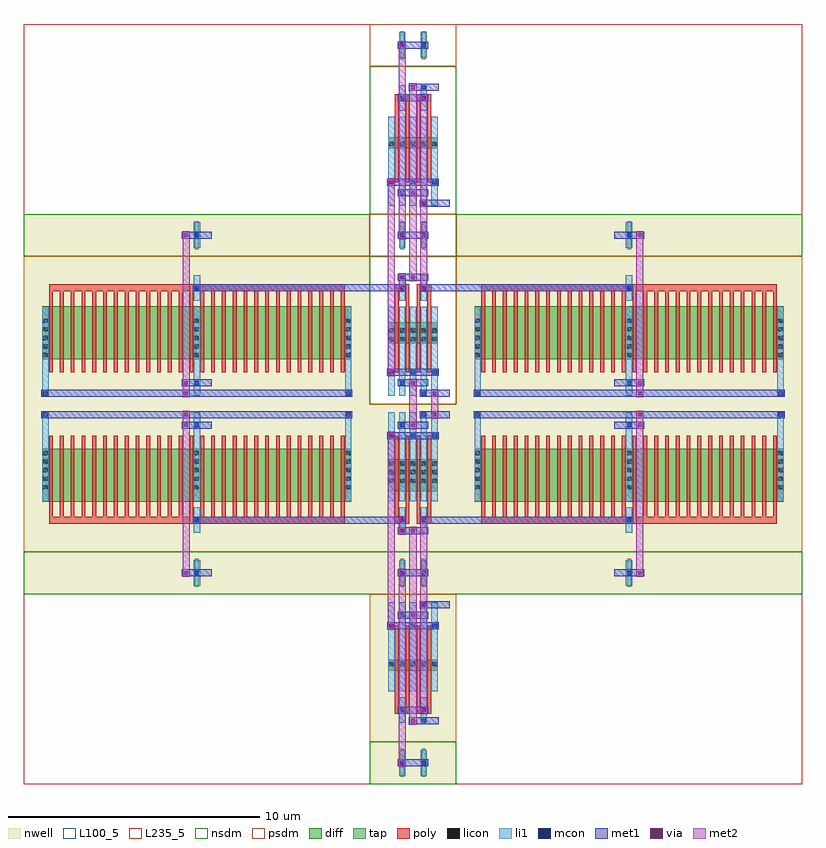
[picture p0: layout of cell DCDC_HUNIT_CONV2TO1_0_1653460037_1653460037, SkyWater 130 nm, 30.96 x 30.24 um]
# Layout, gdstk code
from math import pi, radians
import gdstk
lib = gdstk.Library(unit=1e-6, precision=1e-09)
def R(c, l, rs):  # rectangles x0, y0, x1, y1
    for r in rs: c.add(gdstk.rectangle(r[:2], r[2:], *l))
def A(c, l, x, y, w, h, nx, ny, dx, dy):  # array of equal rectangles
    R(c, l, [(x+i*dx, y+j*dy, x+i*dx+w, y+j*dy+h) for i in range(nx) for j in range(ny)])
def P(c, l, *ps):  # polygons
    for p in ps: c.add(gdstk.Polygon(p, *l))
nwell = (64, 20)
diff = (65, 20)
tap = (65, 44)
poly = (66, 20)
licon = (66, 44)
li1 = (67, 20)
mcon = (67, 44)
met1 = (68, 20)
via = (68, 44)
met2 = (69, 20)
nsdm = (93, 44)
psdm = (94, 20)
L100_5 = (100, 5)
L235_5 = (235, 5)

ccp_pmos_b_53083828_x1_y = lib.new_cell('CCP_PMOS_B_53083828_X1_Y1_1653460036_1653460037_1653460037_1653460037')
R(ccp_pmos_b_53083828_x1_y, nwell, [(0,0,3.44,7.56)])
R(ccp_pmos_b_53083828_x1_y, diff, [(0.735,2.625,2.705,3.045)])
R(ccp_pmos_b_53083828_x1_y, tap, [(1.205,6.16,1.375,7.28), (2.065,6.16,2.235,7.28)])
A(ccp_pmos_b_53083828_x1_y, poly, 1, 1.26, 0.15, 3.36, 4, 1, 0.43, 0)
R(ccp_pmos_b_53083828_x1_y, poly, [(1,4.485,1.58,4.755), (1.86,4.485,2.44,4.755)])
A(ccp_pmos_b_53083828_x1_y, licon, 0.775, 2.705, 0.17, 0.17, 3, 1, 0.43, 0)
A(ccp_pmos_b_53083828_x1_y, licon, 1.635, 2.705, 0.17, 0.17, 3, 1, 0.43, 0)
R(ccp_pmos_b_53083828_x1_y, licon, [(1.205,4.535,1.375,4.705), (2.065,4.535,2.235,4.705), (1.205,6.635,1.375,6.805), (2.065,6.635,2.235,6.805)])
A(ccp_pmos_b_53083828_x1_y, li1, 0.735, 0.335, 0.25, 3.53, 5, 1, 0.43, 0)
R(ccp_pmos_b_53083828_x1_y, li1, [(1.165,4.115,1.415,5.125), (2.025,4.115,2.275,5.125), (1.165,6.215,1.415,7.225), (2.025,6.215,2.275,7.225)])
A(ccp_pmos_b_53083828_x1_y, mcon, 0.775, 1.175, 0.17, 0.17, 3, 1, 0.86, 0)
R(ccp_pmos_b_53083828_x1_y, mcon, [(1.205,0.335,1.375,0.505), (2.065,0.755,2.235,0.925), (2.065,4.535,2.235,4.705), (1.205,4.955,1.375,5.125), (1.205,6.635,1.375,6.805), (2.065,6.635,2.235,6.805)])
R(ccp_pmos_b_53083828_x1_y, met1, [(0.26,0.28,1.46,0.56), (1.12,0.7,2.32,0.98), (0.69,1.12,2.75,1.4), (1.12,4.48,2.32,4.76), (0.69,4.9,1.89,5.18), (1.12,6.58,2.32,6.86)])
R(ccp_pmos_b_53083828_x1_y, via, [(1.215,0.345,1.365,0.495), (1.645,0.765,1.795,0.915), (1.215,4.545,1.365,4.695), (1.645,4.965,1.795,5.115)])
R(ccp_pmos_b_53083828_x1_y, met2, [(1.15,0.26,1.43,4.78), (1.58,0.68,1.86,5.2)])
R(ccp_pmos_b_53083828_x1_y, nsdm, [(0,5.88,3.44,7.56)])
R(ccp_pmos_b_53083828_x1_y, psdm, [(0,0,3.44,5.88)])
R(ccp_pmos_b_53083828_x1_y, L100_5, [(0,0,3.44,7.56)])

dp_pmos_b_25364157_x1_y1 = lib.new_cell('DP_PMOS_B_25364157_X1_Y1_1653460038_1653460037_1653460037_1653460037')
R(dp_pmos_b_25364157_x1_y1, nwell, [(0,0,3.44,7.56)])
R(dp_pmos_b_25364157_x1_y1, diff, [(0.735,2.205,2.705,3.465)])
R(dp_pmos_b_25364157_x1_y1, tap, [(1.205,6.16,1.375,7.28), (2.065,6.16,2.235,7.28)])
A(dp_pmos_b_25364157_x1_y1, poly, 1, 1.26, 0.15, 3.36, 4, 1, 0.43, 0)
R(dp_pmos_b_25364157_x1_y1, poly, [(1,4.485,1.58,4.755), (1.86,4.485,2.44,4.755)])
A(dp_pmos_b_25364157_x1_y1, licon, 0.775, 2.285, 0.17, 0.17, 3, 3, 0.43, 0.34)
A(dp_pmos_b_25364157_x1_y1, licon, 1.635, 2.285, 0.17, 0.17, 3, 3, 0.43, 0.34)
R(dp_pmos_b_25364157_x1_y1, licon, [(1.205,4.535,1.375,4.705), (2.065,4.535,2.235,4.705), (1.205,6.635,1.375,6.805), (2.065,6.635,2.235,6.805)])
A(dp_pmos_b_25364157_x1_y1, li1, 0.735, 0.335, 0.25, 3.53, 5, 1, 0.43, 0)
R(dp_pmos_b_25364157_x1_y1, li1, [(1.165,4.115,1.415,5.125), (2.025,4.115,2.275,5.125), (1.165,6.215,1.415,7.225), (2.025,6.215,2.275,7.225)])
A(dp_pmos_b_25364157_x1_y1, mcon, 0.775, 1.175, 0.17, 0.17, 3, 1, 0.86, 0)
R(dp_pmos_b_25364157_x1_y1, mcon, [(1.205,0.335,1.375,0.505), (2.065,0.755,2.235,0.925), (1.205,4.535,1.375,4.705), (2.065,4.955,2.235,5.125), (1.205,6.635,1.375,6.805), (2.065,6.635,2.235,6.805)])
R(dp_pmos_b_25364157_x1_y1, met1, [(0.26,0.28,1.46,0.56), (1.12,0.7,2.32,0.98), (0.69,1.12,2.75,1.4), (0.26,4.48,1.46,4.76), (1.12,4.9,2.32,5.18), (1.12,6.58,2.32,6.86)])
R(dp_pmos_b_25364157_x1_y1, nsdm, [(0,5.88,3.44,7.56)])
R(dp_pmos_b_25364157_x1_y1, psdm, [(0,0,3.44,5.88)])
R(dp_pmos_b_25364157_x1_y1, L100_5, [(0,0,3.44,7.56)])

dcap_pmos_57222488_x1_y1 = lib.new_cell('DCAP_PMOS_57222488_X1_Y1_1653460037_1653460037_1653460037_1653460037')
R(dcap_pmos_57222488_x1_y1, nwell, [(0,0,13.76,7.56)])
R(dcap_pmos_57222488_x1_y1, diff, [(0.735,1.785,13.025,3.885)])
R(dcap_pmos_57222488_x1_y1, tap, [(6.795,6.16,6.965,7.28)])
A(dcap_pmos_57222488_x1_y1, poly, 1, 1.26, 0.15, 3.36, 28, 1, 0.43, 0)
R(dcap_pmos_57222488_x1_y1, poly, [(1,4.485,12.76,4.755)])
A(dcap_pmos_57222488_x1_y1, licon, 0.775, 1.865, 0.17, 0.17, 3, 5, 6.02, 0.34)
R(dcap_pmos_57222488_x1_y1, licon, [(6.795,4.535,6.965,4.705), (6.795,6.635,6.965,6.805)])
A(dcap_pmos_57222488_x1_y1, li1, 0.735, 0.335, 0.25, 3.53, 3, 1, 6.02, 0)
R(dcap_pmos_57222488_x1_y1, li1, [(6.755,4.115,7.005,5.125), (6.755,6.215,7.005,7.225)])
R(dcap_pmos_57222488_x1_y1, mcon, [(0.775,0.335,0.945,0.505), (12.815,0.335,12.985,0.505), (6.795,0.755,6.965,0.925), (6.795,4.535,6.965,4.705), (6.795,6.635,6.965,6.805)])
R(dcap_pmos_57222488_x1_y1, met1, [(0.69,0.28,13.07,0.56), (6.28,0.7,7.48,0.98), (5.85,4.48,7.05,4.76), (6.28,6.58,7.48,6.86)])
R(dcap_pmos_57222488_x1_y1, via, [(7.235,0.345,7.385,0.495), (7.235,0.765,7.385,0.915), (7.235,6.645,7.385,6.795)])
R(dcap_pmos_57222488_x1_y1, met2, [(7.17,0.26,7.45,6.88)])
R(dcap_pmos_57222488_x1_y1, nsdm, [(0,5.88,13.76,7.56)])
R(dcap_pmos_57222488_x1_y1, psdm, [(0,0,13.76,5.88)])
R(dcap_pmos_57222488_x1_y1, L100_5, [(0,0,13.76,7.56)])

dcdc_xsw_pmos_0_16534600 = lib.new_cell('DCDC_XSW_PMOS_0_1653460037_1653460037_1653460037')
R(dcdc_xsw_pmos_0_16534600, met1, [(14.89,0.7,15.21,0.98), (14.89,0.7,15.21,0.98), (14.46,6.16,14.78,6.44), (14.46,6.16,14.78,6.44), (14.89,8.26,15.21,8.54), (14.89,8.26,15.21,8.54), (14.89,9.94,15.21,10.22), (14.89,9.94,15.21,10.22), (15.32,9.94,15.64,10.22), (15.32,9.94,15.64,10.22), (15.32,9.94,15.64,10.22), (15.32,9.94,15.64,10.22), (7.74,10.36,15.05,10.64), (14.89,10.36,15.21,10.64), (14.89,10.36,15.21,10.64), (15.75,10.36,16.07,10.64), (15.75,10.36,16.07,10.64), (15.75,10.36,16.07,10.64), (15.75,10.36,16.07,10.64), (16.77,10.36,23.22,10.64), (14.46,13.72,14.78,14), (14.46,13.72,14.78,14)])
P(dcdc_xsw_pmos_0_16534600, met1, [(0,0),(0,0),(0,0),(0,0)],
  [(0,0),(0,0),(0,0),(0,0)],
  [(0,0),(0,0),(0,0),(0,0)],
  [(0,0),(0,0),(0,0),(0,0)],
  [(0,0),(0,0),(0,0),(0,0)],
  [(0,0),(0,0),(0,0),(0,0)],
  [(0,0),(0,0),(0,0),(0,0)],
  [(0,0),(0,0),(0,0),(0,0)],
  [(0,0),(0,0),(0,0),(0,0)],
  [(0,0),(0,0),(0,0),(0,0)])
R(dcdc_xsw_pmos_0_16534600, via, [(14.975,0.765,15.125,0.915), (14.975,0.765,15.125,0.915), (14.545,6.225,14.695,6.375), (14.545,6.225,14.695,6.375), (14.975,8.325,15.125,8.475), (14.975,8.325,15.125,8.475), (14.975,10.005,15.125,10.155), (14.975,10.005,15.125,10.155), (15.405,10.005,15.555,10.155), (15.405,10.005,15.555,10.155), (15.405,10.005,15.555,10.155), (15.405,10.005,15.555,10.155), (14.975,10.425,15.125,10.575), (14.975,10.425,15.125,10.575), (15.835,10.425,15.985,10.575), (15.835,10.425,15.985,10.575), (15.835,10.425,15.985,10.575), (15.835,10.425,15.985,10.575), (14.545,13.785,14.695,13.935), (14.545,13.785,14.695,13.935)])
R(dcdc_xsw_pmos_0_16534600, met2, [(14.91,0.68,15.19,1), (14.91,0.68,15.19,1), (14.91,0.84,15.19,8.4), (14.48,6.14,14.76,6.46), (14.48,6.14,14.76,6.46), (14.48,6.3,14.76,13.86), (15.34,6.72,15.62,10.08), (15.77,7.14,16.05,10.5), (14.91,8.24,15.19,8.56), (14.91,8.24,15.19,8.56), (14.91,9.92,15.19,10.24), (14.91,9.92,15.19,10.24), (15.34,9.92,15.62,10.24), (15.34,9.92,15.62,10.24), (15.34,9.92,15.62,10.24), (15.34,9.92,15.62,10.24), (14.91,10.08,15.19,10.5), (14.91,10.34,15.19,10.66), (14.91,10.34,15.19,10.66), (15.77,10.34,16.05,10.66), (15.77,10.34,16.05,10.66), (15.77,10.34,16.05,10.66), (15.77,10.34,16.05,10.66), (14.48,13.7,14.76,14.02), (14.48,13.7,14.76,14.02)])
P(dcdc_xsw_pmos_0_16534600, met2, [(0,0),(0,0),(0,0),(0,0)],
  [(0,0),(0,0),(0,0),(0,0)],
  [(0,0),(0,0),(0,0),(0,0)],
  [(0,0),(0,0),(0,0),(0,0)])
R(dcdc_xsw_pmos_0_16534600, L235_5, [(0,0,30.96,15.12)])
dcdc_xsw_pmos_0_16534600.add(gdstk.Reference(ccp_pmos_b_53083828_x1_y, (17.2,7.56), rotation=pi))
dcdc_xsw_pmos_0_16534600.add(gdstk.Reference(dp_pmos_b_25364157_x1_y1, (17.2,15.12), rotation=pi))
dcdc_xsw_pmos_0_16534600.add(gdstk.Reference(dcap_pmos_57222488_x1_y1, (17.2,15.12), x_reflection=True))
dcdc_xsw_pmos_0_16534600.add(gdstk.Reference(dcap_pmos_57222488_x1_y1, (13.76,15.12), rotation=pi))

ccp_nmos_b_26073270_x1_y = lib.new_cell('CCP_NMOS_B_26073270_X1_Y1_1653460036_1653460036_1653460037_1653460037')
R(ccp_nmos_b_26073270_x1_y, diff, [(0.735,2.625,2.705,3.045)])
R(ccp_nmos_b_26073270_x1_y, tap, [(1.205,6.16,1.375,7.28), (2.065,6.16,2.235,7.28)])
A(ccp_nmos_b_26073270_x1_y, poly, 1, 1.26, 0.15, 3.36, 4, 1, 0.43, 0)
R(ccp_nmos_b_26073270_x1_y, poly, [(1,4.485,1.58,4.755), (1.86,4.485,2.44,4.755)])
A(ccp_nmos_b_26073270_x1_y, licon, 0.775, 2.705, 0.17, 0.17, 3, 1, 0.43, 0)
A(ccp_nmos_b_26073270_x1_y, licon, 1.635, 2.705, 0.17, 0.17, 3, 1, 0.43, 0)
R(ccp_nmos_b_26073270_x1_y, licon, [(1.205,4.535,1.375,4.705), (2.065,4.535,2.235,4.705), (1.205,6.635,1.375,6.805), (2.065,6.635,2.235,6.805)])
A(ccp_nmos_b_26073270_x1_y, li1, 0.735, 0.335, 0.25, 3.53, 5, 1, 0.43, 0)
R(ccp_nmos_b_26073270_x1_y, li1, [(1.165,4.115,1.415,5.125), (2.025,4.115,2.275,5.125), (1.165,6.215,1.415,7.225), (2.025,6.215,2.275,7.225)])
A(ccp_nmos_b_26073270_x1_y, mcon, 0.775, 1.175, 0.17, 0.17, 3, 1, 0.86, 0)
R(ccp_nmos_b_26073270_x1_y, mcon, [(1.205,0.335,1.375,0.505), (2.065,0.755,2.235,0.925), (2.065,4.535,2.235,4.705), (1.205,4.955,1.375,5.125), (1.205,6.635,1.375,6.805), (2.065,6.635,2.235,6.805)])
R(ccp_nmos_b_26073270_x1_y, met1, [(0.26,0.28,1.46,0.56), (1.12,0.7,2.32,0.98), (0.69,1.12,2.75,1.4), (1.12,4.48,2.32,4.76), (0.69,4.9,1.89,5.18), (1.12,6.58,2.32,6.86)])
R(ccp_nmos_b_26073270_x1_y, via, [(1.215,0.345,1.365,0.495), (1.645,0.765,1.795,0.915), (1.215,4.545,1.365,4.695), (1.645,4.965,1.795,5.115)])
R(ccp_nmos_b_26073270_x1_y, met2, [(1.15,0.26,1.43,4.78), (1.58,0.68,1.86,5.2)])
R(ccp_nmos_b_26073270_x1_y, nsdm, [(0,0,3.44,5.88)])
R(ccp_nmos_b_26073270_x1_y, psdm, [(0,5.88,3.44,7.56)])
R(ccp_nmos_b_26073270_x1_y, L100_5, [(0,0,3.44,7.56)])

dp_nmos_b_83449181_x1_y1 = lib.new_cell('DP_NMOS_B_83449181_X1_Y1_1653460038_1653460036_1653460037_1653460037')
R(dp_nmos_b_83449181_x1_y1, diff, [(0.735,2.415,2.705,3.255)])
R(dp_nmos_b_83449181_x1_y1, tap, [(1.205,6.16,1.375,7.28), (2.065,6.16,2.235,7.28)])
A(dp_nmos_b_83449181_x1_y1, poly, 1, 1.26, 0.15, 3.36, 4, 1, 0.43, 0)
R(dp_nmos_b_83449181_x1_y1, poly, [(1,4.485,1.58,4.755), (1.86,4.485,2.44,4.755)])
A(dp_nmos_b_83449181_x1_y1, licon, 0.775, 2.495, 0.17, 0.17, 3, 2, 0.43, 0.34)
A(dp_nmos_b_83449181_x1_y1, licon, 1.635, 2.495, 0.17, 0.17, 3, 2, 0.43, 0.34)
R(dp_nmos_b_83449181_x1_y1, licon, [(1.205,4.535,1.375,4.705), (2.065,4.535,2.235,4.705), (1.205,6.635,1.375,6.805), (2.065,6.635,2.235,6.805)])
A(dp_nmos_b_83449181_x1_y1, li1, 0.735, 0.335, 0.25, 3.53, 5, 1, 0.43, 0)
R(dp_nmos_b_83449181_x1_y1, li1, [(1.165,4.115,1.415,5.125), (2.025,4.115,2.275,5.125), (1.165,6.215,1.415,7.225), (2.025,6.215,2.275,7.225)])
A(dp_nmos_b_83449181_x1_y1, mcon, 0.775, 1.175, 0.17, 0.17, 3, 1, 0.86, 0)
R(dp_nmos_b_83449181_x1_y1, mcon, [(1.205,0.335,1.375,0.505), (2.065,0.755,2.235,0.925), (1.205,4.535,1.375,4.705), (2.065,4.955,2.235,5.125), (1.205,6.635,1.375,6.805), (2.065,6.635,2.235,6.805)])
R(dp_nmos_b_83449181_x1_y1, met1, [(0.26,0.28,1.46,0.56), (1.12,0.7,2.32,0.98), (0.69,1.12,2.75,1.4), (0.26,4.48,1.46,4.76), (1.12,4.9,2.32,5.18), (1.12,6.58,2.32,6.86)])
R(dp_nmos_b_83449181_x1_y1, nsdm, [(0,0,3.44,5.88)])
R(dp_nmos_b_83449181_x1_y1, psdm, [(0,5.88,3.44,7.56)])
R(dp_nmos_b_83449181_x1_y1, L100_5, [(0,0,3.44,7.56)])

c_dcap_pmos_57222488_x1_y1 = lib.new_cell('DCAP_PMOS_57222488_X1_Y1_1653460037_1653460036_1653460037_1653460037')
R(c_dcap_pmos_57222488_x1_y1, nwell, [(0,0,13.76,7.56)])
R(c_dcap_pmos_57222488_x1_y1, diff, [(0.735,1.785,13.025,3.885)])
R(c_dcap_pmos_57222488_x1_y1, tap, [(6.795,6.16,6.965,7.28)])
A(c_dcap_pmos_57222488_x1_y1, poly, 1, 1.26, 0.15, 3.36, 28, 1, 0.43, 0)
R(c_dcap_pmos_57222488_x1_y1, poly, [(1,4.485,12.76,4.755)])
A(c_dcap_pmos_57222488_x1_y1, licon, 0.775, 1.865, 0.17, 0.17, 3, 5, 6.02, 0.34)
R(c_dcap_pmos_57222488_x1_y1, licon, [(6.795,4.535,6.965,4.705), (6.795,6.635,6.965,6.805)])
A(c_dcap_pmos_57222488_x1_y1, li1, 0.735, 0.335, 0.25, 3.53, 3, 1, 6.02, 0)
R(c_dcap_pmos_57222488_x1_y1, li1, [(6.755,4.115,7.005,5.125), (6.755,6.215,7.005,7.225)])
R(c_dcap_pmos_57222488_x1_y1, mcon, [(0.775,0.335,0.945,0.505), (12.815,0.335,12.985,0.505), (6.795,0.755,6.965,0.925), (6.795,4.535,6.965,4.705), (6.795,6.635,6.965,6.805)])
R(c_dcap_pmos_57222488_x1_y1, met1, [(0.69,0.28,13.07,0.56), (6.28,0.7,7.48,0.98), (5.85,4.48,7.05,4.76), (6.28,6.58,7.48,6.86)])
R(c_dcap_pmos_57222488_x1_y1, via, [(7.235,0.345,7.385,0.495), (7.235,0.765,7.385,0.915), (7.235,6.645,7.385,6.795)])
R(c_dcap_pmos_57222488_x1_y1, met2, [(7.17,0.26,7.45,6.88)])
R(c_dcap_pmos_57222488_x1_y1, nsdm, [(0,5.88,13.76,7.56)])
R(c_dcap_pmos_57222488_x1_y1, psdm, [(0,0,13.76,5.88)])
R(c_dcap_pmos_57222488_x1_y1, L100_5, [(0,0,13.76,7.56)])

dcdc_xsw_nmos_0_16534600 = lib.new_cell('DCDC_XSW_NMOS_0_1653460036_1653460037_1653460037')
R(dcdc_xsw_nmos_0_16534600, met1, [(14.89,0.7,15.21,0.98), (14.89,0.7,15.21,0.98), (14.46,6.16,14.78,6.44), (14.46,6.16,14.78,6.44), (14.89,8.26,15.21,8.54), (14.89,8.26,15.21,8.54), (14.89,9.94,15.21,10.22), (14.89,9.94,15.21,10.22), (15.32,9.94,15.64,10.22), (15.32,9.94,15.64,10.22), (15.32,9.94,15.64,10.22), (15.32,9.94,15.64,10.22), (7.74,10.36,15.05,10.64), (14.89,10.36,15.21,10.64), (14.89,10.36,15.21,10.64), (15.75,10.36,16.07,10.64), (15.75,10.36,16.07,10.64), (15.75,10.36,16.07,10.64), (15.75,10.36,16.07,10.64), (16.77,10.36,23.22,10.64), (14.46,13.72,14.78,14), (14.46,13.72,14.78,14)])
P(dcdc_xsw_nmos_0_16534600, met1, [(0,0),(0,0),(0,0),(0,0)],
  [(0,0),(0,0),(0,0),(0,0)],
  [(0,0),(0,0),(0,0),(0,0)],
  [(0,0),(0,0),(0,0),(0,0)],
  [(0,0),(0,0),(0,0),(0,0)],
  [(0,0),(0,0),(0,0),(0,0)],
  [(0,0),(0,0),(0,0),(0,0)],
  [(0,0),(0,0),(0,0),(0,0)],
  [(0,0),(0,0),(0,0),(0,0)],
  [(0,0),(0,0),(0,0),(0,0)])
R(dcdc_xsw_nmos_0_16534600, via, [(14.975,0.765,15.125,0.915), (14.975,0.765,15.125,0.915), (14.545,6.225,14.695,6.375), (14.545,6.225,14.695,6.375), (14.975,8.325,15.125,8.475), (14.975,8.325,15.125,8.475), (14.975,10.005,15.125,10.155), (14.975,10.005,15.125,10.155), (15.405,10.005,15.555,10.155), (15.405,10.005,15.555,10.155), (15.405,10.005,15.555,10.155), (15.405,10.005,15.555,10.155), (14.975,10.425,15.125,10.575), (14.975,10.425,15.125,10.575), (15.835,10.425,15.985,10.575), (15.835,10.425,15.985,10.575), (15.835,10.425,15.985,10.575), (15.835,10.425,15.985,10.575), (14.545,13.785,14.695,13.935), (14.545,13.785,14.695,13.935)])
R(dcdc_xsw_nmos_0_16534600, met2, [(14.91,0.68,15.19,1), (14.91,0.68,15.19,1), (14.91,0.84,15.19,8.4), (14.48,6.14,14.76,6.46), (14.48,6.14,14.76,6.46), (14.48,6.3,14.76,13.86), (15.34,6.72,15.62,10.08), (15.77,7.14,16.05,10.5), (14.91,8.24,15.19,8.56), (14.91,8.24,15.19,8.56), (14.91,9.92,15.19,10.24), (14.91,9.92,15.19,10.24), (15.34,9.92,15.62,10.24), (15.34,9.92,15.62,10.24), (15.34,9.92,15.62,10.24), (15.34,9.92,15.62,10.24), (14.91,10.08,15.19,10.5), (14.91,10.34,15.19,10.66), (14.91,10.34,15.19,10.66), (15.77,10.34,16.05,10.66), (15.77,10.34,16.05,10.66), (15.77,10.34,16.05,10.66), (15.77,10.34,16.05,10.66), (14.48,13.7,14.76,14.02), (14.48,13.7,14.76,14.02)])
P(dcdc_xsw_nmos_0_16534600, met2, [(0,0),(0,0),(0,0),(0,0)],
  [(0,0),(0,0),(0,0),(0,0)],
  [(0,0),(0,0),(0,0),(0,0)],
  [(0,0),(0,0),(0,0),(0,0)])
R(dcdc_xsw_nmos_0_16534600, L235_5, [(0,0,30.96,15.12)])
dcdc_xsw_nmos_0_16534600.add(gdstk.Reference(ccp_nmos_b_26073270_x1_y, (17.2,7.56), rotation=pi))
dcdc_xsw_nmos_0_16534600.add(gdstk.Reference(dp_nmos_b_83449181_x1_y1, (17.2,15.12), rotation=pi))
dcdc_xsw_nmos_0_16534600.add(gdstk.Reference(c_dcap_pmos_57222488_x1_y1, (17.2,15.12), x_reflection=True))
dcdc_xsw_nmos_0_16534600.add(gdstk.Reference(c_dcap_pmos_57222488_x1_y1, (13.76,15.12), rotation=pi))

dcdc_hunit_conv2to1_0_16 = lib.new_cell('DCDC_HUNIT_CONV2TO1_0_1653460037_1653460037')
R(dcdc_hunit_conv2to1_0_16, met1, [(15.32,14.14,15.64,14.42), (15.32,14.14,15.64,14.42), (16.18,14.56,16.5,14.84), (16.18,14.56,16.5,14.84), (16.18,15.4,16.5,15.68), (16.18,15.4,16.5,15.68), (15.32,15.82,15.64,16.1), (15.32,15.82,15.64,16.1)])
P(dcdc_hunit_conv2to1_0_16, met1, [(0,0),(0,0),(0,0),(0,0)],
  [(0,0),(0,0),(0,0),(0,0)],
  [(0,0),(0,0),(0,0),(0,0)],
  [(0,0),(0,0),(0,0),(0,0)],
  [(0,0),(0,0),(0,0),(0,0)],
  [(0,0),(0,0),(0,0),(0,0)],
  [(0,0),(0,0),(0,0),(0,0)],
  [(0,0),(0,0),(0,0),(0,0)],
  [(0,0),(0,0),(0,0),(0,0)],
  [(0,0),(0,0),(0,0),(0,0)],
  [(0,0),(0,0),(0,0),(0,0)],
  [(0,0),(0,0),(0,0),(0,0)],
  [(0,0),(0,0),(0,0),(0,0)],
  [(0,0),(0,0),(0,0),(0,0)],
  [(0,0),(0,0),(0,0),(0,0)],
  [(0,0),(0,0),(0,0),(0,0)],
  [(0,0),(0,0),(0,0),(0,0)],
  [(0,0),(0,0),(0,0),(0,0)],
  [(0,0),(0,0),(0,0),(0,0)],
  [(0,0),(0,0),(0,0),(0,0)])
R(dcdc_hunit_conv2to1_0_16, via, [(15.405,14.205,15.555,14.355), (15.405,14.205,15.555,14.355), (16.265,14.625,16.415,14.775), (16.265,14.625,16.415,14.775), (16.265,15.465,16.415,15.615), (16.265,15.465,16.415,15.615), (15.405,15.885,15.555,16.035), (15.405,15.885,15.555,16.035)])
R(dcdc_hunit_conv2to1_0_16, met2, [(15.34,14.12,15.62,14.44), (15.34,14.12,15.62,14.44), (15.34,14.28,15.62,15.96), (16.2,14.54,16.48,14.86), (16.2,14.54,16.48,14.86), (16.2,14.7,16.48,15.54), (16.2,15.38,16.48,15.7), (16.2,15.38,16.48,15.7), (15.34,15.8,15.62,16.12), (15.34,15.8,15.62,16.12)])
P(dcdc_hunit_conv2to1_0_16, met2, [(0,0),(0,0),(0,0),(0,0)],
  [(0,0),(0,0),(0,0),(0,0)],
  [(0,0),(0,0),(0,0),(0,0)],
  [(0,0),(0,0),(0,0),(0,0)],
  [(0,0),(0,0),(0,0),(0,0)],
  [(0,0),(0,0),(0,0),(0,0)],
  [(0,0),(0,0),(0,0),(0,0)],
  [(0,0),(0,0),(0,0),(0,0)])
R(dcdc_hunit_conv2to1_0_16, L235_5, [(0,0,30.96,30.24)])
dcdc_hunit_conv2to1_0_16.add(gdstk.Reference(dcdc_xsw_pmos_0_16534600, (0,0)))
dcdc_hunit_conv2to1_0_16.add(gdstk.Reference(dcdc_xsw_nmos_0_16534600, (0,30.24), x_reflection=True))

lib.write_gds('DCDC_HUNIT_CONV2TO1_0_1653460037_1653460037.gds')
